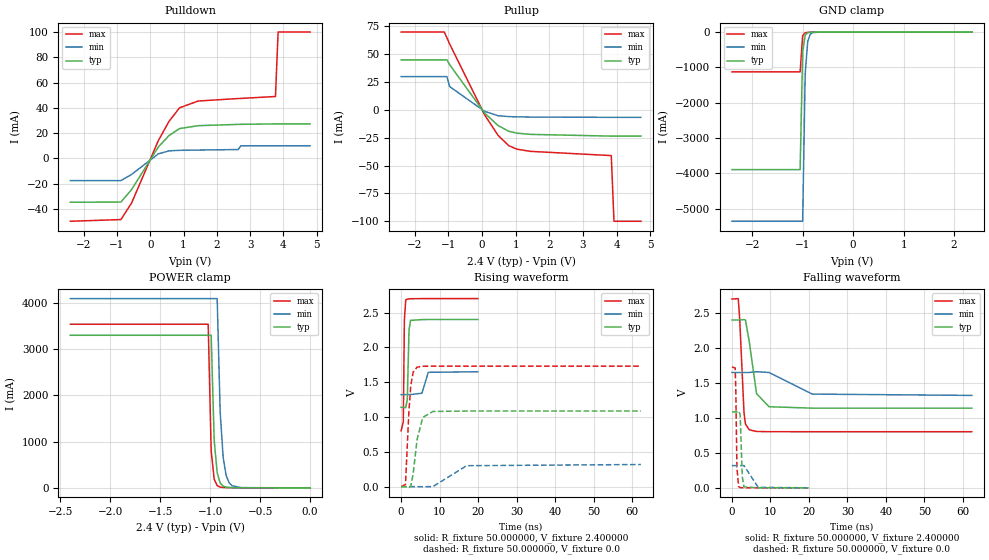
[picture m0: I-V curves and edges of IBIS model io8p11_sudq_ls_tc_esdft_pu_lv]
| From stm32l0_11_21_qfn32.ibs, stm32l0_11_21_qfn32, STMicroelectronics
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|   Model io8p11_sudq_ls_tc_esdft_pu_lv
[Model]  io8p11_sudq_ls_tc_esdft_pu_lv
Model_type I/O
Polarity   Non-Inverting
Enable   Active-Low
Vinl =   0.720000V
Vinh =   1.680000V
Vmeas =  1.200000V
Cref =   50.000000pF
Rref =   100.000000M
Vref =   0.0V
C_comp   2.242700pF   2.201100pF   2.288600pF
[Temperature Range]   25.000000   0.105000k   -40.000000
[Pullup Reference]   2.400000V   1.650000V   2.700000V
[Pulldown Reference]   0.0V   0.0V   0.0V
[POWER Clamp Reference]   2.400000V   1.650000V   2.700000V
[GND Clamp Reference]   0.0V   0.0V   0.0V
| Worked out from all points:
|   slope of the pulldown table from 0 to 0.36 V, typ, clamps not added: 28.4 ohm
|   slope of the pullup table from 0 to 0.36 V, typ, clamps not added: 32.2 ohm
|   GND clamp passes 1 mA (typ) near -0.65 V on its own axis
|   POWER clamp passes 1 mA (typ) near -0.63 V on its own axis
|   rising waveform, R_fixture 50.000000, V_fixture 2.400000: 20-80 % time 282ps typ, 635ps min, 188ps max; typ from 1.14 V to 2.4 V
|   rising waveform, R_fixture 50.000000, V_fixture 0.0: 20-80 % time 1.6ns typ, 3.9ns min, 928ps max; typ from 0.001 V to 1.09 V
|   falling waveform, R_fixture 50.000000, V_fixture 2.400000: 20-80 % time 1.8ns typ, 4.72ns min, 909ps max; typ from 2.4 V to 1.14 V
|   falling waveform, R_fixture 50.000000, V_fixture 0.0: 20-80 % time 359ps typ, 771ps min, 265ps max; typ from 1.09 V to 0.001 V
[Pulldown]
|Voltage   I(typ)   I(min)   I(max)
-2.4V     -34.71mA   -17.61mA   -49.77mA
-880mV    -34.55mA   -17.61mA   -48.41mA
-560mV    -24.66mA   -12.69mA   -35.31mA
240mV     8.893mA    3.542mA    13.9mA
560mV     17.98mA    5.931mA    29.16mA
880mV     23.58mA    6.388mA    40.03mA
1.44V     25.89mA    6.593mA    45.41mA
2.64V     26.92mA    7mA        47.38mA
2.72V     26.96mA    10mA       47.46mA
3.76V     27.3mA     10mA       49mA
3.84V     27.3mA     10mA       100mA
4.8V      27.3mA     10mA       100mA
[Pullup]
|Voltage   I(typ)   I(min)   I(max)
-2.4V     45mA       30mA       70mA
-1.12V    45mA       30mA       70mA
-1.04V    45mA       30mA       64.8mA
-960mV    40.7mA     21mA       59.3mA
80mV      -2.838mA   -1.261mA   -4.478mA
480mV     -14.04mA   -5.167mA   -22.91mA
800mV     -19.2mA    -5.978mA   -32.18mA
1.04V     -20.85mA   -6.184mA   -35.23mA
1.44V     -21.93mA   -6.373mA   -37.19mA
3.84V     -23.5mA    -6.63mA    -41mA
3.92V     -23.5mA    -6.63mA    -100mA
4.72V     -23.5mA    -6.63mA    -100mA
[GND_clamp]
|Voltage   I(typ)   I(min)   I(max)
-2.4V     -3.892A    -5.353A    -1.127A
-1.05V    -3.892A    -5.353A    -1.127A
-1V       -568.8mA   -5.353A    -105.4mA
-950mV    -88.95mA   -1.19A     -18.03mA
-900mV    -18.15mA   -269.2mA   -8.959mA
-850mV    -6.699mA   -63.45mA   -6.568mA
-800mV    -4.014mA   -16.61mA   -4.858mA
-650mV    -1.043mA   -1.218mA   -1.146mA
2.35V     0A         0A         0A
[POWER_clamp]
|Voltage   I(typ)   I(min)   I(max)
-2.4V     3.303A     4.097A     3.542A
-1.02V    3.303A     4.097A     3.542A
-990mV    3.303A     4.097A     802.4mA
-960mV    1.032A     4.097A     186.5mA
-930mV    325.2mA    4.097A     47.6mA
-900mV    104.9mA    1.637A     15.79mA
-870mV    35.84mA    655.7mA    8.024mA
-840mV    13.94mA    263.9mA    5.676mA
-810mV    6.724mA    107.2mA    4.568mA
-780mV    4.1mA      44.41mA    3.772mA
-690mV    1.753mA    4.377mA    1.918mA
0V        0A         0A         0A
[Ramp]
| variable   typ   min   max
dV/dt_r  0.65094/1.59608n   0.19037/3.89991n   1.03799/0.92564n
dV/dt_f  0.75624/1.80017n   0.19656/4.71403n   1.13750/0.90684n
R_load = 50.000000
[Rising Waveform]
R_fixture= 50.000000
V_fixture= 2.400000
V_fixture_min= 1.650000
V_fixture_max= 2.700000
|time   V(typ)   V(min)   V(max)
0s        1.14V      1.322V     803.1mV
560.6ps   1.139V     1.322V     930.1mV
840.8ps   1.136V     1.322V     2.394V
1.201ns   1.136V     1.322V     2.683V
1.602ns   1.257V     1.323V     2.692V
2.042ns   2.249V     1.323V     2.696V
2.442ns   2.387V     1.323V     2.698V
5.405ns   2.399V     1.342V     2.7V
7.047ns   2.4V       1.642V     2.7V
19.94ns   2.4V       1.65V      2.7V
[Rising Waveform]
R_fixture= 50.000000
V_fixture= 0.0
V_fixture_min= 0.0
V_fixture_max= 0.0
|time   V(typ)   V(min)   V(max)
0s        893.1uV    1.345mV    757.3uV
1.126ns   841.8uV    1.34mV     31.5mV
2.002ns   -16.18mV   1.333mV    1.068V
2.503ns   5.083mV    1.376mV    1.453V
3.128ns   188.3mV    1.413mV    1.646V
4.129ns   673.7mV    1.403mV    1.716V
5.631ns   995.9mV    -671.1uV   1.729V
8.258ns   1.08V      2.199mV    1.73V
17.02ns   1.086V     301.7mV    1.73V
62.31ns   1.086V     318.6mV    1.73V
[Falling Waveform]
R_fixture= 50.000000
V_fixture= 2.400000
V_fixture_min= 1.650000
V_fixture_max= 2.700000
|time   V(typ)   V(min)   V(max)
0s        2.4V       1.65V      2.7V
1.627ns   2.4V       1.65V      2.706V
2.002ns   2.401V     1.65V      2.42V
3.128ns   2.406V     1.65V      1.072V
3.504ns   2.4V       1.65V      913mV
4.505ns   2.086V     1.65V      830.5mV
6.381ns   1.347V     1.661V     806.8mV
9.635ns   1.16V      1.65V      803.3mV
20.9ns    1.14V      1.341V     803.1mV
62.31ns   1.14V      1.322V     803.1mV
[Falling Waveform]
R_fixture= 50.000000
V_fixture= 0.0
V_fixture_min= 0.0
V_fixture_max= 0.0
|time   V(typ)   V(min)   V(max)
0s        1.086V     318.6mV    1.73V
840.8ps   1.086V     318.6mV    1.713V
1.001ns   1.086V     318.6mV    1.367V
1.281ns   1.085V     318.6mV    293.1mV
1.722ns   1.099V     318.6mV    18.64mV
2.122ns   1.048V     318.6mV    4.487mV
2.683ns   154.5mV    318.4mV    2.618mV
3.123ns   13.85mV    318.2mV    2.038mV
6.807ns   1.503mV    8.15mV     795.2uV
19.94ns   893.1uV    1.345mV    757.3uV
